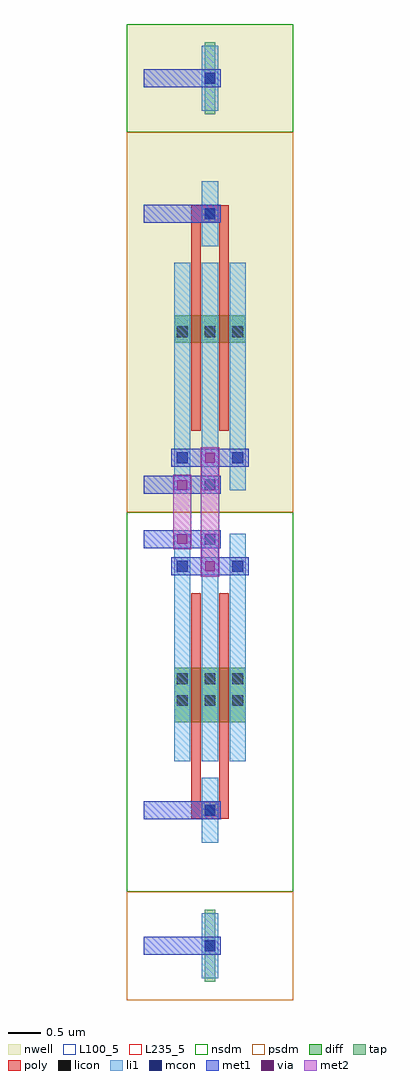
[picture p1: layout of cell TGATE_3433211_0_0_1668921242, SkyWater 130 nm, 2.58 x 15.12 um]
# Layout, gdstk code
import gdstk
lib = gdstk.Library(unit=1e-6, precision=1e-09)
def R(c, l, rs):  # rectangles x0, y0, x1, y1
    for r in rs: c.add(gdstk.rectangle(r[:2], r[2:], *l))
def A(c, l, x, y, w, h, nx, ny, dx, dy):  # array of equal rectangles
    R(c, l, [(x+i*dx, y+j*dy, x+i*dx+w, y+j*dy+h) for i in range(nx) for j in range(ny)])
def P(c, l, *ps):  # polygons
    for p in ps: c.add(gdstk.Polygon(p, *l))
nwell = (64, 20)
diff = (65, 20)
tap = (65, 44)
poly = (66, 20)
licon = (66, 44)
li1 = (67, 20)
mcon = (67, 44)
met1 = (68, 20)
via = (68, 44)
met2 = (69, 20)
nsdm = (93, 44)
psdm = (94, 20)
L100_5 = (100, 5)
L235_5 = (235, 5)

nmos_4t_90354340_x1_y1_1 = lib.new_cell('NMOS_4T_90354340_X1_Y1_1668921235_1668921242')
R(nmos_4t_90354340_x1_y1_1, diff, [(0.735,2.415,1.845,3.255)])
R(nmos_4t_90354340_x1_y1_1, tap, [(1.205,6.16,1.375,7.28)])
R(nmos_4t_90354340_x1_y1_1, poly, [(1,1.26,1.15,4.62), (1.43,1.26,1.58,4.62), (1,4.485,1.58,4.755)])
A(nmos_4t_90354340_x1_y1_1, licon, 0.775, 2.495, 0.17, 0.17, 3, 2, 0.43, 0.34)
R(nmos_4t_90354340_x1_y1_1, licon, [(1.205,4.535,1.375,4.705), (1.205,6.635,1.375,6.805)])
A(nmos_4t_90354340_x1_y1_1, li1, 0.735, 0.335, 0.25, 3.53, 3, 1, 0.43, 0)
R(nmos_4t_90354340_x1_y1_1, li1, [(1.165,4.115,1.415,5.125), (1.165,6.215,1.415,7.225)])
R(nmos_4t_90354340_x1_y1_1, mcon, [(1.205,0.335,1.375,0.505), (0.775,0.755,0.945,0.925), (1.635,0.755,1.805,0.925), (1.205,4.535,1.375,4.705), (1.205,6.635,1.375,6.805)])
R(nmos_4t_90354340_x1_y1_1, met1, [(0.26,0.28,1.46,0.56), (0.69,0.7,1.89,0.98), (0.26,4.48,1.46,4.76), (0.26,6.58,1.46,6.86)])
R(nmos_4t_90354340_x1_y1_1, nsdm, [(0,0,2.58,5.88)])
R(nmos_4t_90354340_x1_y1_1, psdm, [(0,5.88,2.58,7.56)])
R(nmos_4t_90354340_x1_y1_1, L100_5, [(0,0,2.58,7.56)])

pmos_4t_67258562_x1_y1_1 = lib.new_cell('PMOS_4T_67258562_X1_Y1_1668921236_1668921242')
R(pmos_4t_67258562_x1_y1_1, nwell, [(0,0,2.58,7.56)])
R(pmos_4t_67258562_x1_y1_1, diff, [(0.735,2.625,1.845,3.045)])
R(pmos_4t_67258562_x1_y1_1, tap, [(1.205,6.16,1.375,7.28)])
R(pmos_4t_67258562_x1_y1_1, poly, [(1,1.26,1.15,4.62), (1.43,1.26,1.58,4.62), (1,4.485,1.58,4.755)])
A(pmos_4t_67258562_x1_y1_1, licon, 0.775, 2.705, 0.17, 0.17, 3, 1, 0.43, 0)
R(pmos_4t_67258562_x1_y1_1, licon, [(1.205,4.535,1.375,4.705), (1.205,6.635,1.375,6.805)])
A(pmos_4t_67258562_x1_y1_1, li1, 0.735, 0.335, 0.25, 3.53, 3, 1, 0.43, 0)
R(pmos_4t_67258562_x1_y1_1, li1, [(1.165,4.115,1.415,5.125), (1.165,6.215,1.415,7.225)])
R(pmos_4t_67258562_x1_y1_1, mcon, [(1.205,0.335,1.375,0.505), (0.775,0.755,0.945,0.925), (1.635,0.755,1.805,0.925), (1.205,4.535,1.375,4.705), (1.205,6.635,1.375,6.805)])
R(pmos_4t_67258562_x1_y1_1, met1, [(0.26,0.28,1.46,0.56), (0.69,0.7,1.89,0.98), (0.26,4.48,1.46,4.76), (0.26,6.58,1.46,6.86)])
R(pmos_4t_67258562_x1_y1_1, nsdm, [(0,5.88,2.58,7.56)])
R(pmos_4t_67258562_x1_y1_1, psdm, [(0,0,2.58,5.88)])
R(pmos_4t_67258562_x1_y1_1, L100_5, [(0,0,2.58,7.56)])

tgate_3433211_0_0_166892 = lib.new_cell('TGATE_3433211_0_0_1668921242')
R(tgate_3433211_0_0_166892, met1, [(1.13,6.58,1.45,6.86), (1.13,6.58,1.45,6.86), (0.7,7,1.02,7.28), (0.7,7,1.02,7.28), (0.7,7.84,1.02,8.12), (0.7,7.84,1.02,8.12), (1.13,8.26,1.45,8.54), (1.13,8.26,1.45,8.54)])
P(tgate_3433211_0_0_166892, met1, [(0,0),(0,0),(0,0),(0,0)],
  [(0,0),(0,0),(0,0),(0,0)],
  [(0,0),(0,0),(0,0),(0,0)],
  [(0,0),(0,0),(0,0),(0,0)],
  [(0,0),(0,0),(0,0),(0,0)],
  [(0,0),(0,0),(0,0),(0,0)],
  [(0,0),(0,0),(0,0),(0,0)],
  [(0,0),(0,0),(0,0),(0,0)])
R(tgate_3433211_0_0_166892, via, [(1.215,6.645,1.365,6.795), (1.215,6.645,1.365,6.795), (0.785,7.065,0.935,7.215), (0.785,7.065,0.935,7.215), (0.785,7.905,0.935,8.055), (0.785,7.905,0.935,8.055), (1.215,8.325,1.365,8.475), (1.215,8.325,1.365,8.475)])
R(tgate_3433211_0_0_166892, met2, [(1.15,6.56,1.43,6.88), (1.15,6.56,1.43,6.88), (1.15,6.72,1.43,8.4), (0.72,6.98,1,7.3), (0.72,6.98,1,7.3), (0.72,7.14,1,7.98), (0.72,7.82,1,8.14), (0.72,7.82,1,8.14), (1.15,8.24,1.43,8.56), (1.15,8.24,1.43,8.56)])
R(tgate_3433211_0_0_166892, L235_5, [(0,0,2.58,15.12)])
tgate_3433211_0_0_166892.add(gdstk.Reference(nmos_4t_90354340_x1_y1_1, (0,7.56), x_reflection=True))
tgate_3433211_0_0_166892.add(gdstk.Reference(pmos_4t_67258562_x1_y1_1, (0,7.56)))

lib.write_gds('TGATE_3433211_0_0_1668921242.gds')
